VERSION 5.8 ;
BUSBITCHARS "[]" ;
DIVIDERCHAR "/" ;

UNITS
  DATABASE MICRONS 2000 ;
END UNITS

MANUFACTURINGGRID 0.0010 ;

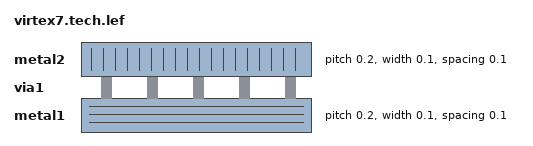
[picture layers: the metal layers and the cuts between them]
LAYER metal1
  TYPE ROUTING ;
  DIRECTION HORIZONTAL ;
  WIDTH 0.10 ;
  SPACING 0.10 ;
  PITCH 0.20 ;
  RESISTANCE RPERSQ 0.10 ;
  CAPACITANCE CPERSQDIST 1.0e-04 ;
END metal1

LAYER via1
  TYPE CUT ;
END via1

LAYER metal2
  TYPE ROUTING ;
  DIRECTION VERTICAL ;
  WIDTH 0.10 ;
  SPACING 0.10 ;
  PITCH 0.20 ;
  RESISTANCE RPERSQ 0.10 ;
  CAPACITANCE CPERSQDIST 1.0e-04 ;
END metal2

SITE SLICE
  CLASS CORE ;
  SYMMETRY Y ;
  SIZE 1.000 BY 1.000 ;
END SLICE

SITE BRAM
  CLASS CORE ;
  SYMMETRY Y ;
  SIZE 1.000 BY 1.000 ;
END BRAM

SITE DSP
  CLASS CORE ;
  SYMMETRY Y ;
  SIZE 1.000 BY 1.000 ;
END DSP

SITE IO
  CLASS PAD ;
  SYMMETRY Y ;
  SIZE 1.000 BY 1.000 ;
END IO

SITE CLK
  CLASS CORE ;
  SYMMETRY Y ;
  SIZE 1.000 BY 1.000 ;
END CLK

